VERSION 5.7 ;
  NOWIREEXTENSIONATPIN ON ;
  DIVIDERCHAR "/" ;
  BUSBITCHARS "[]" ;
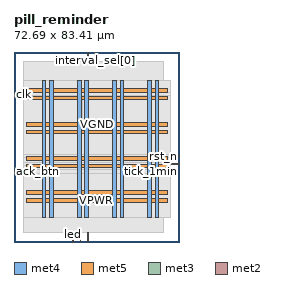
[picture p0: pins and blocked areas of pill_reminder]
MACRO pill_reminder
  CLASS BLOCK ;
  FOREIGN pill_reminder ;
  ORIGIN 0.000 0.000 ;
  SIZE 72.690 BY 83.410 ;
  PIN VGND
    DIRECTION INOUT ;
    USE GROUND ;
    PORT
      LAYER met4 ;
        RECT 15.725 10.640 17.325 70.960 ;
    END
    PORT
      LAYER met4 ;
        RECT 31.135 10.640 32.735 70.960 ;
    END
    PORT
      LAYER met4 ;
        RECT 46.545 10.640 48.145 70.960 ;
    END
    PORT
      LAYER met4 ;
        RECT 61.955 10.640 63.555 70.960 ;
    END
    PORT
      LAYER met5 ;
        RECT 5.280 20.855 67.400 22.455 ;
    END
    PORT
      LAYER met5 ;
        RECT 5.280 35.810 67.400 37.410 ;
    END
    PORT
      LAYER met5 ;
        RECT 5.280 50.765 67.400 52.365 ;
    END
    PORT
      LAYER met5 ;
        RECT 5.280 65.720 67.400 67.320 ;
    END
  END VGND
  PIN VPWR
    DIRECTION INOUT ;
    USE POWER ;
    PORT
      LAYER met4 ;
        RECT 12.425 10.640 14.025 70.960 ;
    END
    PORT
      LAYER met4 ;
        RECT 27.835 10.640 29.435 70.960 ;
    END
    PORT
      LAYER met4 ;
        RECT 43.245 10.640 44.845 70.960 ;
    END
    PORT
      LAYER met4 ;
        RECT 58.655 10.640 60.255 70.960 ;
    END
    PORT
      LAYER met5 ;
        RECT 5.280 17.555 67.400 19.155 ;
    END
    PORT
      LAYER met5 ;
        RECT 5.280 32.510 67.400 34.110 ;
    END
    PORT
      LAYER met5 ;
        RECT 5.280 47.465 67.400 49.065 ;
    END
    PORT
      LAYER met5 ;
        RECT 5.280 62.420 67.400 64.020 ;
    END
  END VPWR
  PIN ack_btn
    DIRECTION INPUT ;
    USE SIGNAL ;
    ANTENNAGATEAREA 0.196500 ;
    PORT
      LAYER met3 ;
        RECT 0.000 30.640 4.000 31.240 ;
    END
  END ack_btn
  PIN buzzer
    DIRECTION OUTPUT ;
    USE SIGNAL ;
    ANTENNADIFFAREA 0.383400 ;
    PORT
      LAYER met2 ;
        RECT 32.290 0.000 32.570 4.000 ;
    END
  END buzzer
  PIN clk
    DIRECTION INPUT ;
    USE SIGNAL ;
    ANTENNAGATEAREA 0.852000 ;
    PORT
      LAYER met3 ;
        RECT 0.000 64.640 4.000 65.240 ;
    END
  END clk
  PIN interval_sel[0]
    DIRECTION INPUT ;
    USE SIGNAL ;
    ANTENNAGATEAREA 0.196500 ;
    PORT
      LAYER met2 ;
        RECT 35.510 79.410 35.790 83.410 ;
    END
  END interval_sel[0]
  PIN interval_sel[1]
    DIRECTION INPUT ;
    USE SIGNAL ;
    ANTENNAGATEAREA 0.196500 ;
    PORT
      LAYER met2 ;
        RECT 32.290 79.410 32.570 83.410 ;
    END
  END interval_sel[1]
  PIN led
    DIRECTION OUTPUT ;
    USE SIGNAL ;
    ANTENNADIFFAREA 0.383400 ;
    PORT
      LAYER met2 ;
        RECT 25.850 0.000 26.130 4.000 ;
    END
  END led
  PIN missed_dose_flag
    DIRECTION OUTPUT ;
    USE SIGNAL ;
    ANTENNADIFFAREA 0.383400 ;
    PORT
      LAYER met2 ;
        RECT 29.070 0.000 29.350 4.000 ;
    END
  END missed_dose_flag
  PIN rst_n
    DIRECTION INPUT ;
    USE SIGNAL ;
    ANTENNAGATEAREA 0.196500 ;
    PORT
      LAYER met3 ;
        RECT 68.690 37.440 72.690 38.040 ;
    END
  END rst_n
  PIN tick_1min
    DIRECTION INPUT ;
    USE SIGNAL ;
    ANTENNAGATEAREA 0.159000 ;
    PORT
      LAYER met3 ;
        RECT 68.690 34.040 72.690 34.640 ;
    END
  END tick_1min
  OBS
      LAYER nwell ;
        RECT 5.330 10.795 67.350 70.805 ;
      LAYER li1 ;
        RECT 5.520 10.795 67.160 70.805 ;
      LAYER met1 ;
        RECT 4.210 10.640 67.160 70.960 ;
      LAYER met2 ;
        RECT 4.230 79.130 32.010 79.410 ;
        RECT 32.850 79.130 35.230 79.410 ;
        RECT 36.070 79.130 65.690 79.410 ;
        RECT 4.230 4.280 65.690 79.130 ;
        RECT 4.230 4.000 25.570 4.280 ;
        RECT 26.410 4.000 28.790 4.280 ;
        RECT 29.630 4.000 32.010 4.280 ;
        RECT 32.850 4.000 65.690 4.280 ;
      LAYER met3 ;
        RECT 3.990 65.640 68.690 70.885 ;
        RECT 4.400 64.240 68.690 65.640 ;
        RECT 3.990 38.440 68.690 64.240 ;
        RECT 3.990 37.040 68.290 38.440 ;
        RECT 3.990 35.040 68.690 37.040 ;
        RECT 3.990 33.640 68.290 35.040 ;
        RECT 3.990 31.640 68.690 33.640 ;
        RECT 4.400 30.240 68.690 31.640 ;
        RECT 3.990 10.715 68.690 30.240 ;
      LAYER met4 ;
        RECT 29.835 47.775 30.065 64.425 ;
  END
END pill_reminder
END LIBRARY

